VERSION 5.7 ;
BUSBITCHARS "[]" ;
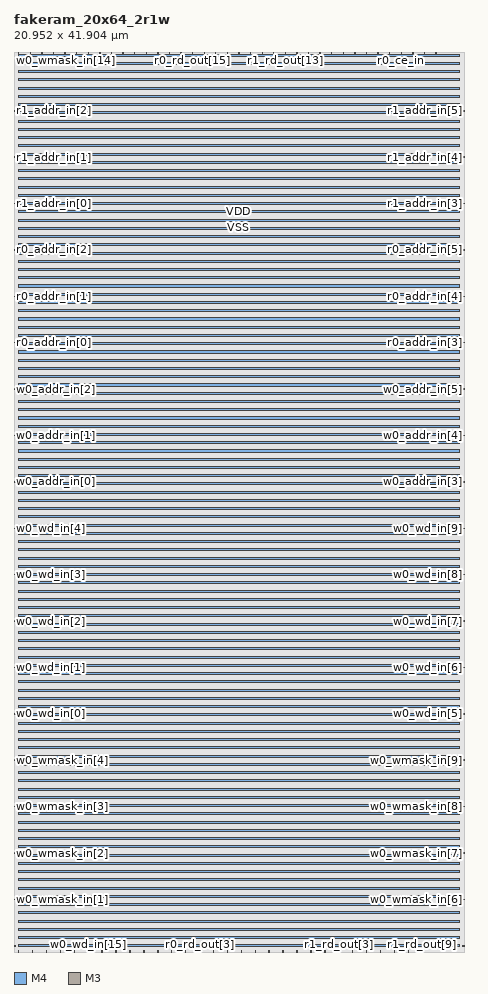
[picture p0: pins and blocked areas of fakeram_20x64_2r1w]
MACRO fakeram_20x64_2r1w
  FOREIGN fakeram_20x64_2r1w 0 0 ;
  SYMMETRY X Y R90 ;
  SIZE 20.952 BY 41.904 ;
  CLASS BLOCK ;
  PIN w0_wmask_in[0]
    DIRECTION INPUT ;
    USE SIGNAL ;
    SHAPE ABUTMENT ;
    PORT
      LAYER M4 ;
      RECT 0.000 0.276 0.072 0.300 ;
    END
  END w0_wmask_in[0]
  PIN w0_wmask_in[1]
    DIRECTION INPUT ;
    USE SIGNAL ;
    SHAPE ABUTMENT ;
    PORT
      LAYER M4 ;
      RECT 0.000 2.436 0.072 2.460 ;
    END
  END w0_wmask_in[1]
  PIN w0_wmask_in[2]
    DIRECTION INPUT ;
    USE SIGNAL ;
    SHAPE ABUTMENT ;
    PORT
      LAYER M4 ;
      RECT 0.000 4.596 0.072 4.620 ;
    END
  END w0_wmask_in[2]
  PIN w0_wmask_in[3]
    DIRECTION INPUT ;
    USE SIGNAL ;
    SHAPE ABUTMENT ;
    PORT
      LAYER M4 ;
      RECT 0.000 6.756 0.072 6.780 ;
    END
  END w0_wmask_in[3]
  PIN w0_wmask_in[4]
    DIRECTION INPUT ;
    USE SIGNAL ;
    SHAPE ABUTMENT ;
    PORT
      LAYER M4 ;
      RECT 0.000 8.916 0.072 8.940 ;
    END
  END w0_wmask_in[4]
  PIN w0_wmask_in[5]
    DIRECTION INPUT ;
    USE SIGNAL ;
    SHAPE ABUTMENT ;
    PORT
      LAYER M4 ;
      RECT 20.880 0.276 20.952 0.300 ;
    END
  END w0_wmask_in[5]
  PIN w0_wmask_in[6]
    DIRECTION INPUT ;
    USE SIGNAL ;
    SHAPE ABUTMENT ;
    PORT
      LAYER M4 ;
      RECT 20.880 2.436 20.952 2.460 ;
    END
  END w0_wmask_in[6]
  PIN w0_wmask_in[7]
    DIRECTION INPUT ;
    USE SIGNAL ;
    SHAPE ABUTMENT ;
    PORT
      LAYER M4 ;
      RECT 20.880 4.596 20.952 4.620 ;
    END
  END w0_wmask_in[7]
  PIN w0_wmask_in[8]
    DIRECTION INPUT ;
    USE SIGNAL ;
    SHAPE ABUTMENT ;
    PORT
      LAYER M4 ;
      RECT 20.880 6.756 20.952 6.780 ;
    END
  END w0_wmask_in[8]
  PIN w0_wmask_in[9]
    DIRECTION INPUT ;
    USE SIGNAL ;
    SHAPE ABUTMENT ;
    PORT
      LAYER M4 ;
      RECT 20.880 8.916 20.952 8.940 ;
    END
  END w0_wmask_in[9]
  PIN w0_wmask_in[10]
    DIRECTION INPUT ;
    USE SIGNAL ;
    SHAPE ABUTMENT ;
    PORT
      LAYER M3 ;
      RECT 0.207 41.850 0.225 41.904 ;
    END
  END w0_wmask_in[10]
  PIN w0_wmask_in[11]
    DIRECTION INPUT ;
    USE SIGNAL ;
    SHAPE ABUTMENT ;
    PORT
      LAYER M3 ;
      RECT 0.747 41.850 0.765 41.904 ;
    END
  END w0_wmask_in[11]
  PIN w0_wmask_in[12]
    DIRECTION INPUT ;
    USE SIGNAL ;
    SHAPE ABUTMENT ;
    PORT
      LAYER M3 ;
      RECT 1.287 41.850 1.305 41.904 ;
    END
  END w0_wmask_in[12]
  PIN w0_wmask_in[13]
    DIRECTION INPUT ;
    USE SIGNAL ;
    SHAPE ABUTMENT ;
    PORT
      LAYER M3 ;
      RECT 1.827 41.850 1.845 41.904 ;
    END
  END w0_wmask_in[13]
  PIN w0_wmask_in[14]
    DIRECTION INPUT ;
    USE SIGNAL ;
    SHAPE ABUTMENT ;
    PORT
      LAYER M3 ;
      RECT 2.367 41.850 2.385 41.904 ;
    END
  END w0_wmask_in[14]
  PIN w0_wmask_in[15]
    DIRECTION INPUT ;
    USE SIGNAL ;
    SHAPE ABUTMENT ;
    PORT
      LAYER M3 ;
      RECT 2.907 41.850 2.925 41.904 ;
    END
  END w0_wmask_in[15]
  PIN w0_wmask_in[16]
    DIRECTION INPUT ;
    USE SIGNAL ;
    SHAPE ABUTMENT ;
    PORT
      LAYER M3 ;
      RECT 3.447 41.850 3.465 41.904 ;
    END
  END w0_wmask_in[16]
  PIN w0_wmask_in[17]
    DIRECTION INPUT ;
    USE SIGNAL ;
    SHAPE ABUTMENT ;
    PORT
      LAYER M3 ;
      RECT 3.987 41.850 4.005 41.904 ;
    END
  END w0_wmask_in[17]
  PIN w0_wmask_in[18]
    DIRECTION INPUT ;
    USE SIGNAL ;
    SHAPE ABUTMENT ;
    PORT
      LAYER M3 ;
      RECT 4.527 41.850 4.545 41.904 ;
    END
  END w0_wmask_in[18]
  PIN w0_wmask_in[19]
    DIRECTION INPUT ;
    USE SIGNAL ;
    SHAPE ABUTMENT ;
    PORT
      LAYER M3 ;
      RECT 5.067 41.850 5.085 41.904 ;
    END
  END w0_wmask_in[19]
  PIN w0_wd_in[0]
    DIRECTION INPUT ;
    USE SIGNAL ;
    SHAPE ABUTMENT ;
    PORT
      LAYER M4 ;
      RECT 0.000 11.076 0.072 11.100 ;
    END
  END w0_wd_in[0]
  PIN w0_wd_in[1]
    DIRECTION INPUT ;
    USE SIGNAL ;
    SHAPE ABUTMENT ;
    PORT
      LAYER M4 ;
      RECT 0.000 13.236 0.072 13.260 ;
    END
  END w0_wd_in[1]
  PIN w0_wd_in[2]
    DIRECTION INPUT ;
    USE SIGNAL ;
    SHAPE ABUTMENT ;
    PORT
      LAYER M4 ;
      RECT 0.000 15.396 0.072 15.420 ;
    END
  END w0_wd_in[2]
  PIN w0_wd_in[3]
    DIRECTION INPUT ;
    USE SIGNAL ;
    SHAPE ABUTMENT ;
    PORT
      LAYER M4 ;
      RECT 0.000 17.556 0.072 17.580 ;
    END
  END w0_wd_in[3]
  PIN w0_wd_in[4]
    DIRECTION INPUT ;
    USE SIGNAL ;
    SHAPE ABUTMENT ;
    PORT
      LAYER M4 ;
      RECT 0.000 19.716 0.072 19.740 ;
    END
  END w0_wd_in[4]
  PIN w0_wd_in[5]
    DIRECTION INPUT ;
    USE SIGNAL ;
    SHAPE ABUTMENT ;
    PORT
      LAYER M4 ;
      RECT 20.880 11.076 20.952 11.100 ;
    END
  END w0_wd_in[5]
  PIN w0_wd_in[6]
    DIRECTION INPUT ;
    USE SIGNAL ;
    SHAPE ABUTMENT ;
    PORT
      LAYER M4 ;
      RECT 20.880 13.236 20.952 13.260 ;
    END
  END w0_wd_in[6]
  PIN w0_wd_in[7]
    DIRECTION INPUT ;
    USE SIGNAL ;
    SHAPE ABUTMENT ;
    PORT
      LAYER M4 ;
      RECT 20.880 15.396 20.952 15.420 ;
    END
  END w0_wd_in[7]
  PIN w0_wd_in[8]
    DIRECTION INPUT ;
    USE SIGNAL ;
    SHAPE ABUTMENT ;
    PORT
      LAYER M4 ;
      RECT 20.880 17.556 20.952 17.580 ;
    END
  END w0_wd_in[8]
  PIN w0_wd_in[9]
    DIRECTION INPUT ;
    USE SIGNAL ;
    SHAPE ABUTMENT ;
    PORT
      LAYER M4 ;
      RECT 20.880 19.716 20.952 19.740 ;
    END
  END w0_wd_in[9]
  PIN w0_wd_in[10]
    DIRECTION INPUT ;
    USE SIGNAL ;
    SHAPE ABUTMENT ;
    PORT
      LAYER M3 ;
      RECT 0.207 0.000 0.225 0.054 ;
    END
  END w0_wd_in[10]
  PIN w0_wd_in[11]
    DIRECTION INPUT ;
    USE SIGNAL ;
    SHAPE ABUTMENT ;
    PORT
      LAYER M3 ;
      RECT 0.855 0.000 0.873 0.054 ;
    END
  END w0_wd_in[11]
  PIN w0_wd_in[12]
    DIRECTION INPUT ;
    USE SIGNAL ;
    SHAPE ABUTMENT ;
    PORT
      LAYER M3 ;
      RECT 1.503 0.000 1.521 0.054 ;
    END
  END w0_wd_in[12]
  PIN w0_wd_in[13]
    DIRECTION INPUT ;
    USE SIGNAL ;
    SHAPE ABUTMENT ;
    PORT
      LAYER M3 ;
      RECT 2.151 0.000 2.169 0.054 ;
    END
  END w0_wd_in[13]
  PIN w0_wd_in[14]
    DIRECTION INPUT ;
    USE SIGNAL ;
    SHAPE ABUTMENT ;
    PORT
      LAYER M3 ;
      RECT 2.799 0.000 2.817 0.054 ;
    END
  END w0_wd_in[14]
  PIN w0_wd_in[15]
    DIRECTION INPUT ;
    USE SIGNAL ;
    SHAPE ABUTMENT ;
    PORT
      LAYER M3 ;
      RECT 3.447 0.000 3.465 0.054 ;
    END
  END w0_wd_in[15]
  PIN w0_wd_in[16]
    DIRECTION INPUT ;
    USE SIGNAL ;
    SHAPE ABUTMENT ;
    PORT
      LAYER M3 ;
      RECT 4.095 0.000 4.113 0.054 ;
    END
  END w0_wd_in[16]
  PIN w0_wd_in[17]
    DIRECTION INPUT ;
    USE SIGNAL ;
    SHAPE ABUTMENT ;
    PORT
      LAYER M3 ;
      RECT 4.743 0.000 4.761 0.054 ;
    END
  END w0_wd_in[17]
  PIN w0_wd_in[18]
    DIRECTION INPUT ;
    USE SIGNAL ;
    SHAPE ABUTMENT ;
    PORT
      LAYER M3 ;
      RECT 5.391 0.000 5.409 0.054 ;
    END
  END w0_wd_in[18]
  PIN w0_wd_in[19]
    DIRECTION INPUT ;
    USE SIGNAL ;
    SHAPE ABUTMENT ;
    PORT
      LAYER M3 ;
      RECT 6.039 0.000 6.057 0.054 ;
    END
  END w0_wd_in[19]
  PIN r0_rd_out[0]
    DIRECTION OUTPUT ;
    USE SIGNAL ;
    SHAPE ABUTMENT ;
    PORT
      LAYER M3 ;
      RECT 6.687 0.000 6.705 0.054 ;
    END
  END r0_rd_out[0]
  PIN r0_rd_out[1]
    DIRECTION OUTPUT ;
    USE SIGNAL ;
    SHAPE ABUTMENT ;
    PORT
      LAYER M3 ;
      RECT 7.335 0.000 7.353 0.054 ;
    END
  END r0_rd_out[1]
  PIN r0_rd_out[2]
    DIRECTION OUTPUT ;
    USE SIGNAL ;
    SHAPE ABUTMENT ;
    PORT
      LAYER M3 ;
      RECT 7.983 0.000 8.001 0.054 ;
    END
  END r0_rd_out[2]
  PIN r0_rd_out[3]
    DIRECTION OUTPUT ;
    USE SIGNAL ;
    SHAPE ABUTMENT ;
    PORT
      LAYER M3 ;
      RECT 8.631 0.000 8.649 0.054 ;
    END
  END r0_rd_out[3]
  PIN r0_rd_out[4]
    DIRECTION OUTPUT ;
    USE SIGNAL ;
    SHAPE ABUTMENT ;
    PORT
      LAYER M3 ;
      RECT 9.279 0.000 9.297 0.054 ;
    END
  END r0_rd_out[4]
  PIN r0_rd_out[5]
    DIRECTION OUTPUT ;
    USE SIGNAL ;
    SHAPE ABUTMENT ;
    PORT
      LAYER M3 ;
      RECT 9.927 0.000 9.945 0.054 ;
    END
  END r0_rd_out[5]
  PIN r0_rd_out[6]
    DIRECTION OUTPUT ;
    USE SIGNAL ;
    SHAPE ABUTMENT ;
    PORT
      LAYER M3 ;
      RECT 10.575 0.000 10.593 0.054 ;
    END
  END r0_rd_out[6]
  PIN r0_rd_out[7]
    DIRECTION OUTPUT ;
    USE SIGNAL ;
    SHAPE ABUTMENT ;
    PORT
      LAYER M3 ;
      RECT 11.223 0.000 11.241 0.054 ;
    END
  END r0_rd_out[7]
  PIN r0_rd_out[8]
    DIRECTION OUTPUT ;
    USE SIGNAL ;
    SHAPE ABUTMENT ;
    PORT
      LAYER M3 ;
      RECT 11.871 0.000 11.889 0.054 ;
    END
  END r0_rd_out[8]
  PIN r0_rd_out[9]
    DIRECTION OUTPUT ;
    USE SIGNAL ;
    SHAPE ABUTMENT ;
    PORT
      LAYER M3 ;
      RECT 12.519 0.000 12.537 0.054 ;
    END
  END r0_rd_out[9]
  PIN r0_rd_out[10]
    DIRECTION OUTPUT ;
    USE SIGNAL ;
    SHAPE ABUTMENT ;
    PORT
      LAYER M3 ;
      RECT 5.607 41.850 5.625 41.904 ;
    END
  END r0_rd_out[10]
  PIN r0_rd_out[11]
    DIRECTION OUTPUT ;
    USE SIGNAL ;
    SHAPE ABUTMENT ;
    PORT
      LAYER M3 ;
      RECT 6.147 41.850 6.165 41.904 ;
    END
  END r0_rd_out[11]
  PIN r0_rd_out[12]
    DIRECTION OUTPUT ;
    USE SIGNAL ;
    SHAPE ABUTMENT ;
    PORT
      LAYER M3 ;
      RECT 6.687 41.850 6.705 41.904 ;
    END
  END r0_rd_out[12]
  PIN r0_rd_out[13]
    DIRECTION OUTPUT ;
    USE SIGNAL ;
    SHAPE ABUTMENT ;
    PORT
      LAYER M3 ;
      RECT 7.227 41.850 7.245 41.904 ;
    END
  END r0_rd_out[13]
  PIN r0_rd_out[14]
    DIRECTION OUTPUT ;
    USE SIGNAL ;
    SHAPE ABUTMENT ;
    PORT
      LAYER M3 ;
      RECT 7.767 41.850 7.785 41.904 ;
    END
  END r0_rd_out[14]
  PIN r0_rd_out[15]
    DIRECTION OUTPUT ;
    USE SIGNAL ;
    SHAPE ABUTMENT ;
    PORT
      LAYER M3 ;
      RECT 8.307 41.850 8.325 41.904 ;
    END
  END r0_rd_out[15]
  PIN r0_rd_out[16]
    DIRECTION OUTPUT ;
    USE SIGNAL ;
    SHAPE ABUTMENT ;
    PORT
      LAYER M3 ;
      RECT 8.847 41.850 8.865 41.904 ;
    END
  END r0_rd_out[16]
  PIN r0_rd_out[17]
    DIRECTION OUTPUT ;
    USE SIGNAL ;
    SHAPE ABUTMENT ;
    PORT
      LAYER M3 ;
      RECT 9.387 41.850 9.405 41.904 ;
    END
  END r0_rd_out[17]
  PIN r0_rd_out[18]
    DIRECTION OUTPUT ;
    USE SIGNAL ;
    SHAPE ABUTMENT ;
    PORT
      LAYER M3 ;
      RECT 9.927 41.850 9.945 41.904 ;
    END
  END r0_rd_out[18]
  PIN r0_rd_out[19]
    DIRECTION OUTPUT ;
    USE SIGNAL ;
    SHAPE ABUTMENT ;
    PORT
      LAYER M3 ;
      RECT 10.467 41.850 10.485 41.904 ;
    END
  END r0_rd_out[19]
  PIN r1_rd_out[0]
    DIRECTION OUTPUT ;
    USE SIGNAL ;
    SHAPE ABUTMENT ;
    PORT
      LAYER M3 ;
      RECT 13.167 0.000 13.185 0.054 ;
    END
  END r1_rd_out[0]
  PIN r1_rd_out[1]
    DIRECTION OUTPUT ;
    USE SIGNAL ;
    SHAPE ABUTMENT ;
    PORT
      LAYER M3 ;
      RECT 13.815 0.000 13.833 0.054 ;
    END
  END r1_rd_out[1]
  PIN r1_rd_out[2]
    DIRECTION OUTPUT ;
    USE SIGNAL ;
    SHAPE ABUTMENT ;
    PORT
      LAYER M3 ;
      RECT 14.463 0.000 14.481 0.054 ;
    END
  END r1_rd_out[2]
  PIN r1_rd_out[3]
    DIRECTION OUTPUT ;
    USE SIGNAL ;
    SHAPE ABUTMENT ;
    PORT
      LAYER M3 ;
      RECT 15.111 0.000 15.129 0.054 ;
    END
  END r1_rd_out[3]
  PIN r1_rd_out[4]
    DIRECTION OUTPUT ;
    USE SIGNAL ;
    SHAPE ABUTMENT ;
    PORT
      LAYER M3 ;
      RECT 15.759 0.000 15.777 0.054 ;
    END
  END r1_rd_out[4]
  PIN r1_rd_out[5]
    DIRECTION OUTPUT ;
    USE SIGNAL ;
    SHAPE ABUTMENT ;
    PORT
      LAYER M3 ;
      RECT 16.407 0.000 16.425 0.054 ;
    END
  END r1_rd_out[5]
  PIN r1_rd_out[6]
    DIRECTION OUTPUT ;
    USE SIGNAL ;
    SHAPE ABUTMENT ;
    PORT
      LAYER M3 ;
      RECT 17.055 0.000 17.073 0.054 ;
    END
  END r1_rd_out[6]
  PIN r1_rd_out[7]
    DIRECTION OUTPUT ;
    USE SIGNAL ;
    SHAPE ABUTMENT ;
    PORT
      LAYER M3 ;
      RECT 17.703 0.000 17.721 0.054 ;
    END
  END r1_rd_out[7]
  PIN r1_rd_out[8]
    DIRECTION OUTPUT ;
    USE SIGNAL ;
    SHAPE ABUTMENT ;
    PORT
      LAYER M3 ;
      RECT 18.351 0.000 18.369 0.054 ;
    END
  END r1_rd_out[8]
  PIN r1_rd_out[9]
    DIRECTION OUTPUT ;
    USE SIGNAL ;
    SHAPE ABUTMENT ;
    PORT
      LAYER M3 ;
      RECT 18.999 0.000 19.017 0.054 ;
    END
  END r1_rd_out[9]
  PIN r1_rd_out[10]
    DIRECTION OUTPUT ;
    USE SIGNAL ;
    SHAPE ABUTMENT ;
    PORT
      LAYER M3 ;
      RECT 11.007 41.850 11.025 41.904 ;
    END
  END r1_rd_out[10]
  PIN r1_rd_out[11]
    DIRECTION OUTPUT ;
    USE SIGNAL ;
    SHAPE ABUTMENT ;
    PORT
      LAYER M3 ;
      RECT 11.547 41.850 11.565 41.904 ;
    END
  END r1_rd_out[11]
  PIN r1_rd_out[12]
    DIRECTION OUTPUT ;
    USE SIGNAL ;
    SHAPE ABUTMENT ;
    PORT
      LAYER M3 ;
      RECT 12.087 41.850 12.105 41.904 ;
    END
  END r1_rd_out[12]
  PIN r1_rd_out[13]
    DIRECTION OUTPUT ;
    USE SIGNAL ;
    SHAPE ABUTMENT ;
    PORT
      LAYER M3 ;
      RECT 12.627 41.850 12.645 41.904 ;
    END
  END r1_rd_out[13]
  PIN r1_rd_out[14]
    DIRECTION OUTPUT ;
    USE SIGNAL ;
    SHAPE ABUTMENT ;
    PORT
      LAYER M3 ;
      RECT 13.167 41.850 13.185 41.904 ;
    END
  END r1_rd_out[14]
  PIN r1_rd_out[15]
    DIRECTION OUTPUT ;
    USE SIGNAL ;
    SHAPE ABUTMENT ;
    PORT
      LAYER M3 ;
      RECT 13.707 41.850 13.725 41.904 ;
    END
  END r1_rd_out[15]
  PIN r1_rd_out[16]
    DIRECTION OUTPUT ;
    USE SIGNAL ;
    SHAPE ABUTMENT ;
    PORT
      LAYER M3 ;
      RECT 14.247 41.850 14.265 41.904 ;
    END
  END r1_rd_out[16]
  PIN r1_rd_out[17]
    DIRECTION OUTPUT ;
    USE SIGNAL ;
    SHAPE ABUTMENT ;
    PORT
      LAYER M3 ;
      RECT 14.787 41.850 14.805 41.904 ;
    END
  END r1_rd_out[17]
  PIN r1_rd_out[18]
    DIRECTION OUTPUT ;
    USE SIGNAL ;
    SHAPE ABUTMENT ;
    PORT
      LAYER M3 ;
      RECT 15.327 41.850 15.345 41.904 ;
    END
  END r1_rd_out[18]
  PIN r1_rd_out[19]
    DIRECTION OUTPUT ;
    USE SIGNAL ;
    SHAPE ABUTMENT ;
    PORT
      LAYER M3 ;
      RECT 15.867 41.850 15.885 41.904 ;
    END
  END r1_rd_out[19]
  PIN w0_addr_in[0]
    DIRECTION INPUT ;
    USE SIGNAL ;
    SHAPE ABUTMENT ;
    PORT
      LAYER M4 ;
      RECT 0.000 21.876 0.072 21.900 ;
    END
  END w0_addr_in[0]
  PIN w0_addr_in[1]
    DIRECTION INPUT ;
    USE SIGNAL ;
    SHAPE ABUTMENT ;
    PORT
      LAYER M4 ;
      RECT 0.000 24.036 0.072 24.060 ;
    END
  END w0_addr_in[1]
  PIN w0_addr_in[2]
    DIRECTION INPUT ;
    USE SIGNAL ;
    SHAPE ABUTMENT ;
    PORT
      LAYER M4 ;
      RECT 0.000 26.196 0.072 26.220 ;
    END
  END w0_addr_in[2]
  PIN w0_addr_in[3]
    DIRECTION INPUT ;
    USE SIGNAL ;
    SHAPE ABUTMENT ;
    PORT
      LAYER M4 ;
      RECT 20.880 21.876 20.952 21.900 ;
    END
  END w0_addr_in[3]
  PIN w0_addr_in[4]
    DIRECTION INPUT ;
    USE SIGNAL ;
    SHAPE ABUTMENT ;
    PORT
      LAYER M4 ;
      RECT 20.880 24.036 20.952 24.060 ;
    END
  END w0_addr_in[4]
  PIN w0_addr_in[5]
    DIRECTION INPUT ;
    USE SIGNAL ;
    SHAPE ABUTMENT ;
    PORT
      LAYER M4 ;
      RECT 20.880 26.196 20.952 26.220 ;
    END
  END w0_addr_in[5]
  PIN r0_addr_in[0]
    DIRECTION INPUT ;
    USE SIGNAL ;
    SHAPE ABUTMENT ;
    PORT
      LAYER M4 ;
      RECT 0.000 28.356 0.072 28.380 ;
    END
  END r0_addr_in[0]
  PIN r0_addr_in[1]
    DIRECTION INPUT ;
    USE SIGNAL ;
    SHAPE ABUTMENT ;
    PORT
      LAYER M4 ;
      RECT 0.000 30.516 0.072 30.540 ;
    END
  END r0_addr_in[1]
  PIN r0_addr_in[2]
    DIRECTION INPUT ;
    USE SIGNAL ;
    SHAPE ABUTMENT ;
    PORT
      LAYER M4 ;
      RECT 0.000 32.676 0.072 32.700 ;
    END
  END r0_addr_in[2]
  PIN r0_addr_in[3]
    DIRECTION INPUT ;
    USE SIGNAL ;
    SHAPE ABUTMENT ;
    PORT
      LAYER M4 ;
      RECT 20.880 28.356 20.952 28.380 ;
    END
  END r0_addr_in[3]
  PIN r0_addr_in[4]
    DIRECTION INPUT ;
    USE SIGNAL ;
    SHAPE ABUTMENT ;
    PORT
      LAYER M4 ;
      RECT 20.880 30.516 20.952 30.540 ;
    END
  END r0_addr_in[4]
  PIN r0_addr_in[5]
    DIRECTION INPUT ;
    USE SIGNAL ;
    SHAPE ABUTMENT ;
    PORT
      LAYER M4 ;
      RECT 20.880 32.676 20.952 32.700 ;
    END
  END r0_addr_in[5]
  PIN r1_addr_in[0]
    DIRECTION INPUT ;
    USE SIGNAL ;
    SHAPE ABUTMENT ;
    PORT
      LAYER M4 ;
      RECT 0.000 34.836 0.072 34.860 ;
    END
  END r1_addr_in[0]
  PIN r1_addr_in[1]
    DIRECTION INPUT ;
    USE SIGNAL ;
    SHAPE ABUTMENT ;
    PORT
      LAYER M4 ;
      RECT 0.000 36.996 0.072 37.020 ;
    END
  END r1_addr_in[1]
  PIN r1_addr_in[2]
    DIRECTION INPUT ;
    USE SIGNAL ;
    SHAPE ABUTMENT ;
    PORT
      LAYER M4 ;
      RECT 0.000 39.156 0.072 39.180 ;
    END
  END r1_addr_in[2]
  PIN r1_addr_in[3]
    DIRECTION INPUT ;
    USE SIGNAL ;
    SHAPE ABUTMENT ;
    PORT
      LAYER M4 ;
      RECT 20.880 34.836 20.952 34.860 ;
    END
  END r1_addr_in[3]
  PIN r1_addr_in[4]
    DIRECTION INPUT ;
    USE SIGNAL ;
    SHAPE ABUTMENT ;
    PORT
      LAYER M4 ;
      RECT 20.880 36.996 20.952 37.020 ;
    END
  END r1_addr_in[4]
  PIN r1_addr_in[5]
    DIRECTION INPUT ;
    USE SIGNAL ;
    SHAPE ABUTMENT ;
    PORT
      LAYER M4 ;
      RECT 20.880 39.156 20.952 39.180 ;
    END
  END r1_addr_in[5]
  PIN w0_we_in
    DIRECTION INPUT ;
    USE SIGNAL ;
    SHAPE ABUTMENT ;
    PORT
      LAYER M3 ;
      RECT 16.407 41.850 16.425 41.904 ;
    END
  END w0_we_in
  PIN w0_ce_in
    DIRECTION INPUT ;
    USE SIGNAL ;
    SHAPE ABUTMENT ;
    PORT
      LAYER M3 ;
      RECT 16.947 41.850 16.965 41.904 ;
    END
  END w0_ce_in
  PIN w0_clk
    DIRECTION INPUT ;
    USE SIGNAL ;
    SHAPE ABUTMENT ;
    PORT
      LAYER M3 ;
      RECT 17.487 41.850 17.505 41.904 ;
    END
  END w0_clk
  PIN r0_ce_in
    DIRECTION INPUT ;
    USE SIGNAL ;
    SHAPE ABUTMENT ;
    PORT
      LAYER M3 ;
      RECT 18.027 41.850 18.045 41.904 ;
    END
  END r0_ce_in
  PIN r0_clk
    DIRECTION INPUT ;
    USE SIGNAL ;
    SHAPE ABUTMENT ;
    PORT
      LAYER M3 ;
      RECT 18.567 41.850 18.585 41.904 ;
    END
  END r0_clk
  PIN r1_ce_in
    DIRECTION INPUT ;
    USE SIGNAL ;
    SHAPE ABUTMENT ;
    PORT
      LAYER M3 ;
      RECT 19.107 41.850 19.125 41.904 ;
    END
  END r1_ce_in
  PIN r1_clk
    DIRECTION INPUT ;
    USE SIGNAL ;
    SHAPE ABUTMENT ;
    PORT
      LAYER M3 ;
      RECT 19.647 41.850 19.665 41.904 ;
    END
  END r1_clk
  PIN VSS
    DIRECTION INOUT ;
    USE GROUND ;
    PORT
      LAYER M4 ;
      RECT 0.216 0.240 20.736 0.336 ;
      RECT 0.216 1.008 20.736 1.104 ;
      RECT 0.216 1.776 20.736 1.872 ;
      RECT 0.216 2.544 20.736 2.640 ;
      RECT 0.216 3.312 20.736 3.408 ;
      RECT 0.216 4.080 20.736 4.176 ;
      RECT 0.216 4.848 20.736 4.944 ;
      RECT 0.216 5.616 20.736 5.712 ;
      RECT 0.216 6.384 20.736 6.480 ;
      RECT 0.216 7.152 20.736 7.248 ;
      RECT 0.216 7.920 20.736 8.016 ;
      RECT 0.216 8.688 20.736 8.784 ;
      RECT 0.216 9.456 20.736 9.552 ;
      RECT 0.216 10.224 20.736 10.320 ;
      RECT 0.216 10.992 20.736 11.088 ;
      RECT 0.216 11.760 20.736 11.856 ;
      RECT 0.216 12.528 20.736 12.624 ;
      RECT 0.216 13.296 20.736 13.392 ;
      RECT 0.216 14.064 20.736 14.160 ;
      RECT 0.216 14.832 20.736 14.928 ;
      RECT 0.216 15.600 20.736 15.696 ;
      RECT 0.216 16.368 20.736 16.464 ;
      RECT 0.216 17.136 20.736 17.232 ;
      RECT 0.216 17.904 20.736 18.000 ;
      RECT 0.216 18.672 20.736 18.768 ;
      RECT 0.216 19.440 20.736 19.536 ;
      RECT 0.216 20.208 20.736 20.304 ;
      RECT 0.216 20.976 20.736 21.072 ;
      RECT 0.216 21.744 20.736 21.840 ;
      RECT 0.216 22.512 20.736 22.608 ;
      RECT 0.216 23.280 20.736 23.376 ;
      RECT 0.216 24.048 20.736 24.144 ;
      RECT 0.216 24.816 20.736 24.912 ;
      RECT 0.216 25.584 20.736 25.680 ;
      RECT 0.216 26.352 20.736 26.448 ;
      RECT 0.216 27.120 20.736 27.216 ;
      RECT 0.216 27.888 20.736 27.984 ;
      RECT 0.216 28.656 20.736 28.752 ;
      RECT 0.216 29.424 20.736 29.520 ;
      RECT 0.216 30.192 20.736 30.288 ;
      RECT 0.216 30.960 20.736 31.056 ;
      RECT 0.216 31.728 20.736 31.824 ;
      RECT 0.216 32.496 20.736 32.592 ;
      RECT 0.216 33.264 20.736 33.360 ;
      RECT 0.216 34.032 20.736 34.128 ;
      RECT 0.216 34.800 20.736 34.896 ;
      RECT 0.216 35.568 20.736 35.664 ;
      RECT 0.216 36.336 20.736 36.432 ;
      RECT 0.216 37.104 20.736 37.200 ;
      RECT 0.216 37.872 20.736 37.968 ;
      RECT 0.216 38.640 20.736 38.736 ;
      RECT 0.216 39.408 20.736 39.504 ;
      RECT 0.216 40.176 20.736 40.272 ;
      RECT 0.216 40.944 20.736 41.040 ;
      RECT 0.216 41.712 20.736 41.808 ;
    END
  END VSS
  PIN VDD
    DIRECTION INOUT ;
    USE POWER ;
    PORT
      LAYER M4 ;
      RECT 0.216 0.624 20.736 0.720 ;
      RECT 0.216 1.392 20.736 1.488 ;
      RECT 0.216 2.160 20.736 2.256 ;
      RECT 0.216 2.928 20.736 3.024 ;
      RECT 0.216 3.696 20.736 3.792 ;
      RECT 0.216 4.464 20.736 4.560 ;
      RECT 0.216 5.232 20.736 5.328 ;
      RECT 0.216 6.000 20.736 6.096 ;
      RECT 0.216 6.768 20.736 6.864 ;
      RECT 0.216 7.536 20.736 7.632 ;
      RECT 0.216 8.304 20.736 8.400 ;
      RECT 0.216 9.072 20.736 9.168 ;
      RECT 0.216 9.840 20.736 9.936 ;
      RECT 0.216 10.608 20.736 10.704 ;
      RECT 0.216 11.376 20.736 11.472 ;
      RECT 0.216 12.144 20.736 12.240 ;
      RECT 0.216 12.912 20.736 13.008 ;
      RECT 0.216 13.680 20.736 13.776 ;
      RECT 0.216 14.448 20.736 14.544 ;
      RECT 0.216 15.216 20.736 15.312 ;
      RECT 0.216 15.984 20.736 16.080 ;
      RECT 0.216 16.752 20.736 16.848 ;
      RECT 0.216 17.520 20.736 17.616 ;
      RECT 0.216 18.288 20.736 18.384 ;
      RECT 0.216 19.056 20.736 19.152 ;
      RECT 0.216 19.824 20.736 19.920 ;
      RECT 0.216 20.592 20.736 20.688 ;
      RECT 0.216 21.360 20.736 21.456 ;
      RECT 0.216 22.128 20.736 22.224 ;
      RECT 0.216 22.896 20.736 22.992 ;
      RECT 0.216 23.664 20.736 23.760 ;
      RECT 0.216 24.432 20.736 24.528 ;
      RECT 0.216 25.200 20.736 25.296 ;
      RECT 0.216 25.968 20.736 26.064 ;
      RECT 0.216 26.736 20.736 26.832 ;
      RECT 0.216 27.504 20.736 27.600 ;
      RECT 0.216 28.272 20.736 28.368 ;
      RECT 0.216 29.040 20.736 29.136 ;
      RECT 0.216 29.808 20.736 29.904 ;
      RECT 0.216 30.576 20.736 30.672 ;
      RECT 0.216 31.344 20.736 31.440 ;
      RECT 0.216 32.112 20.736 32.208 ;
      RECT 0.216 32.880 20.736 32.976 ;
      RECT 0.216 33.648 20.736 33.744 ;
      RECT 0.216 34.416 20.736 34.512 ;
      RECT 0.216 35.184 20.736 35.280 ;
      RECT 0.216 35.952 20.736 36.048 ;
      RECT 0.216 36.720 20.736 36.816 ;
      RECT 0.216 37.488 20.736 37.584 ;
      RECT 0.216 38.256 20.736 38.352 ;
      RECT 0.216 39.024 20.736 39.120 ;
      RECT 0.216 39.792 20.736 39.888 ;
      RECT 0.216 40.560 20.736 40.656 ;
      RECT 0.216 41.328 20.736 41.424 ;
    END
  END VDD
  OBS
    LAYER M1 ;
    RECT 0 0 20.952 41.904 ;
    LAYER M2 ;
    RECT 0 0 20.952 41.904 ;
    LAYER M3 ;
    RECT 0 0 20.952 41.904 ;
    LAYER M4 ;
    RECT 0 0 20.952 41.904 ;
  END
END fakeram_20x64_2r1w

END LIBRARY
